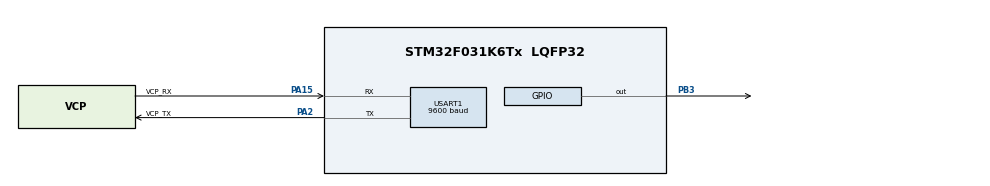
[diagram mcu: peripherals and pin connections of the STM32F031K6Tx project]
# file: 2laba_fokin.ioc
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Mcu.Family=STM32F0
Mcu.Name=STM32F031K6Tx
Mcu.Package=LQFP32
NVIC.USART1_IRQn=true\:0\:0\:false\:false\:true\:true\:true
PA13.GPIO_Label=SWDIO
PA13.Signal=SYS_SWDIO
PA14.GPIO_Label=SWCLK
PA14.Signal=SYS_SWCLK
PA15.GPIO_Label=VCP_RX
PA15.Mode=Asynchronous
PA15.Signal=USART1_RX
PA2.GPIO_Label=VCP_TX
PA2.Mode=Asynchronous
PA2.Signal=USART1_TX
PB3.Signal=GPIO_Output
PF0-OSC_IN.Mode=HSE-External-Oscillator
PF0-OSC_IN.Signal=RCC_OSC_IN
PF1-OSC_OUT.Mode=HSE-External-Oscillator
PF1-OSC_OUT.Signal=RCC_OSC_OUT
ProjectManager.HeapSize=0x200
ProjectManager.StackSize=0x400
ProjectManager.TargetToolchain=STM32CubeIDE
USART1.BaudRate=9600
USART1.VirtualMode-Asynchronous=VM_ASYNC
board=NUCLEO-F031K6

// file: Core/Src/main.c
/* USER CODE BEGIN Header */
/**
  ******************************************************************************
  * @file           : main.c
  * @brief          : Main program body
  ******************************************************************************
  * @attention
  *
  * <h2><center>&copy; Copyright (c) 2020 STMicroelectronics.
  * All rights reserved.</center></h2>
  *
  * This software component is licensed by ST under BSD 3-Clause license,
  * the "License"; You may not use this file except in compliance with the
  * License. You may obtain a copy of the License at:
  *                        opensource.org/licenses/BSD-3-Clause
  *
  ******************************************************************************
  */
/* USER CODE END Header */

#include "main.h"

/* USER CODE BEGIN PD */
#define _countof(a) (sizeof(a)/sizeof(*(a)))
#define DEFAULT_GPIO_DELAY (1000)

#define DEFAULT_GPIO_TOGGLES 5
/* USER CODE END PD */

UART_HandleTypeDef huart1;

void SystemClock_Config(void);
static void MX_GPIO_Init(void);
static void MX_USART1_UART_Init(void);
/* USER CODE BEGIN PFP */
uint8_t GetCommand();

uint8_t GetBlinksCount();

void BlinkNTimesWithDelay(
	uint8_t  uiBlinks,
	uint32_t uiDelay   /* mseconds */
);

uint32_t atoi(uint8_t* pszNumber);

_Bool IsDigit(uint8_t uiByte);

_Bool IsNumber(uint8_t* pszString);

void PrintNewLine();
/* USER CODE END PFP */

int main(void)
{

  /* MCU Configuration--------------------------------------------------------*/

  /* Reset of all peripherals, Initializes the Flash interface and the Systick. */
  HAL_Init();

  /* Configure the system clock */
  SystemClock_Config();

  /* Initialize all configured peripherals */
  MX_GPIO_Init();
  MX_USART1_UART_Init();
  /* USER CODE BEGIN 2 */
int delay_800 = 800;
HAL_Delay(5000);
  /* USER CODE END 2 */

  /* Infinite loop */
  while (1)
  {

    /* USER CODE BEGIN 3 */
	  uint8_t uiCommand = GetCommand();
	  switch(uiCommand)
	  	  {
	  		  case '1':
	  		  {
	  			  int n;
				  n = HAL_GetTick() % 12 + 1;	/* random is here!!1! */
				  BlinkNTimesWithDelay(
				  	  			      n,
									  delay_800
				  	  			  );
	  			  uint8_t uiBlinks = GetBlinksCount();
	  			  if(uiBlinks == n){
			uint8_t pszMessage[] = "\r\nright number";

			HAL_UART_Transmit(
				&huart1,
				pszMessage,
				_countof(pszMessage),
				HAL_MAX_DELAY
			);
	  			  } else{
	  				uint8_t pszMessage[] = "\r\nthat is wrong number";

	  				HAL_UART_Transmit(
	  					&huart1,
	  					pszMessage,
	  					_countof(pszMessage),
	  					HAL_MAX_DELAY
	  				);
	  		  			  }

	  			  break;
	  		  }
	  		case '2':
	  				  {
	  					  goto SILENCE;
	  				  }
	  				  default:
	  				  {
	  					  uint8_t pszErrorMessage[] = \
	  							  "\r\nYou've entered wrong command. Try again\r\n";

	  					  HAL_UART_Transmit(
	  					      &huart1,
	  						  pszErrorMessage,
	  						  _countof(pszErrorMessage),
	  						  HAL_MAX_DELAY
	  					  );

	  					  continue;
	  				  }
	  			  }
	  		  }

	  		SILENCE:	  		  ;

	  		  uint8_t pszFinalMessage[] = \
	  		  	  	  "\r\n\r\nService stopped! Reconnect to run again\r\n";

	  		  HAL_UART_Transmit(
	  		      &huart1,
	  			  pszFinalMessage,
	  			  _countof(pszFinalMessage),
	  			  HAL_MAX_DELAY
	  		  );

	  		  while(1)	  			  ;

  /* USER CODE END 3 */
}

void SystemClock_Config(void)
{
  RCC_OscInitTypeDef RCC_OscInitStruct = {0};
  RCC_ClkInitTypeDef RCC_ClkInitStruct = {0};
  RCC_PeriphCLKInitTypeDef PeriphClkInit = {0};

  /** Initializes the CPU, AHB and APB busses clocks
  */
  RCC_OscInitStruct.OscillatorType = RCC_OSCILLATORTYPE_HSE;
  RCC_OscInitStruct.HSEState = RCC_HSE_ON;
  RCC_OscInitStruct.PLL.PLLState = RCC_PLL_ON;
  RCC_OscInitStruct.PLL.PLLSource = RCC_PLLSOURCE_HSE;
  RCC_OscInitStruct.PLL.PLLMUL = RCC_PLL_MUL4;
  RCC_OscInitStruct.PLL.PREDIV = RCC_PREDIV_DIV1;
  if (HAL_RCC_OscConfig(&RCC_OscInitStruct) != HAL_OK)
  {
    Error_Handler();
  }
  /** Initializes the CPU, AHB and APB busses clocks
  */
  RCC_ClkInitStruct.ClockType = RCC_CLOCKTYPE_HCLK|RCC_CLOCKTYPE_SYSCLK
                              |RCC_CLOCKTYPE_PCLK1;
  RCC_ClkInitStruct.SYSCLKSource = RCC_SYSCLKSOURCE_PLLCLK;
  RCC_ClkInitStruct.AHBCLKDivider = RCC_SYSCLK_DIV1;
  RCC_ClkInitStruct.APB1CLKDivider = RCC_HCLK_DIV1;

  if (HAL_RCC_ClockConfig(&RCC_ClkInitStruct, FLASH_LATENCY_1) != HAL_OK)
  {
    Error_Handler();
  }
  PeriphClkInit.PeriphClockSelection = RCC_PERIPHCLK_USART1;
  PeriphClkInit.Usart1ClockSelection = RCC_USART1CLKSOURCE_PCLK1;
  if (HAL_RCCEx_PeriphCLKConfig(&PeriphClkInit) != HAL_OK)
  {
    Error_Handler();
  }
}

static void MX_USART1_UART_Init(void)
{

  huart1.Instance = USART1;
  huart1.Init.BaudRate = 38400;
  huart1.Init.WordLength = UART_WORDLENGTH_8B;
  huart1.Init.StopBits = UART_STOPBITS_1;
  huart1.Init.Parity = UART_PARITY_NONE;
  huart1.Init.Mode = UART_MODE_TX_RX;
  huart1.Init.HwFlowCtl = UART_HWCONTROL_NONE;
  huart1.Init.OverSampling = UART_OVERSAMPLING_16;
  huart1.Init.OneBitSampling = UART_ONE_BIT_SAMPLE_DISABLE;
  huart1.AdvancedInit.AdvFeatureInit = UART_ADVFEATURE_NO_INIT;
  if (HAL_UART_Init(&huart1) != HAL_OK)
  {
    Error_Handler();
  }

}

static void MX_GPIO_Init(void)
{
  GPIO_InitTypeDef GPIO_InitStruct = {0};

  /* GPIO Ports Clock Enable */
  __HAL_RCC_GPIOF_CLK_ENABLE();
  __HAL_RCC_GPIOA_CLK_ENABLE();
  __HAL_RCC_GPIOB_CLK_ENABLE();

  /*Configure GPIO pin Output Level */
  HAL_GPIO_WritePin(GPIOB, GPIO_PIN_3, GPIO_PIN_RESET);

  /*Configure GPIO pin : PB3 */
  GPIO_InitStruct.Pin = GPIO_PIN_3;
  GPIO_InitStruct.Mode = GPIO_MODE_OUTPUT_PP;
  GPIO_InitStruct.Pull = GPIO_NOPULL;
  GPIO_InitStruct.Speed = GPIO_SPEED_FREQ_LOW;
  HAL_GPIO_Init(GPIOB, &GPIO_InitStruct);

}

/* USER CODE BEGIN 4 */
uint8_t GetCommand()
{
	uint8_t pszMenu[] = \
			"\r\n1) start new game" \
			"\r\n2) Stop listening for commands" \
			"\r\nInput > ";

	HAL_UART_Transmit(
		&huart1,
		pszMenu,
		_countof(pszMenu),
		HAL_MAX_DELAY
	);

	uint8_t cmd[1] = { 0 };

	HAL_UART_Receive(
		&huart1,
		cmd,
		_countof(cmd),
		HAL_MAX_DELAY
	);

	HAL_UART_Transmit(
		&huart1,
		cmd,
		_countof(cmd),
		HAL_MAX_DELAY
	);

	PrintNewLine();

	return cmd[0];
}

uint8_t GetBlinksCount()
{
	uint8_t pszMessage[] = "\r\nEnter the number:";
	HAL_UART_Transmit(
		&huart1,
		pszMessage,
		_countof(pszMessage),
		HAL_MAX_DELAY
	);

	uint8_t pszCount[3] = { 0, 0, 0 };

	uint8_t pszPs[] = "\r\nInput > ";
	do
	{
		HAL_UART_Transmit(
			&huart1,
			pszPs,
			_countof(pszPs),
			HAL_MAX_DELAY
		);

		HAL_UART_Receive(
			&huart1,
			pszCount,
			_countof(pszCount) - 1,
			HAL_MAX_DELAY
		);

		HAL_UART_Transmit(
			&huart1,
			pszCount,
			_countof(pszCount) - 1,
			HAL_MAX_DELAY
		);

		PrintNewLine();

	} while(!IsNumber(pszCount));

	return (uint8_t)atoi(pszCount);
}

void BlinkNTimesWithDelay(
	uint8_t  uiBlinks,
	uint32_t uiDelay /* mseconds */
)
{
	for (uint8_t i = 0; i < uiBlinks; i++)
	{
		HAL_GPIO_TogglePin(GPIOB, GPIO_PIN_3);
		HAL_Delay(uiDelay / 2);
	}
}

uint32_t atoi(uint8_t* pszNumber)
{
    uint32_t uiResult = 0;

    for (int i = 0; pszNumber[i]; i++) {
    	uiResult = uiResult * 10 + (pszNumber[i] - '0');
    }

    return uiResult;
}

_Bool IsDigit(uint8_t uiByte)
{
	return (_Bool)('0' <= uiByte && uiByte <= '9');
}

_Bool IsNumber(uint8_t* pszString)
{
	for(uint8_t i = 0; pszString[i]; i++)
	{
		if (!IsDigit(pszString[i])) {
			return (_Bool)0;
		}
	}
	return (_Bool)1;
}

void PrintNewLine()
{
	uint8_t pszNewLine[] = { '\r', '\n' };

	HAL_UART_Transmit(
		&huart1,
		pszNewLine,
		_countof(pszNewLine),
		HAL_MAX_DELAY
	);
}
/* USER CODE END 4 */

void Error_Handler(void)
{
}

/************************ (C) COPYRIGHT STMicroelectronics *****END OF FILE****/
